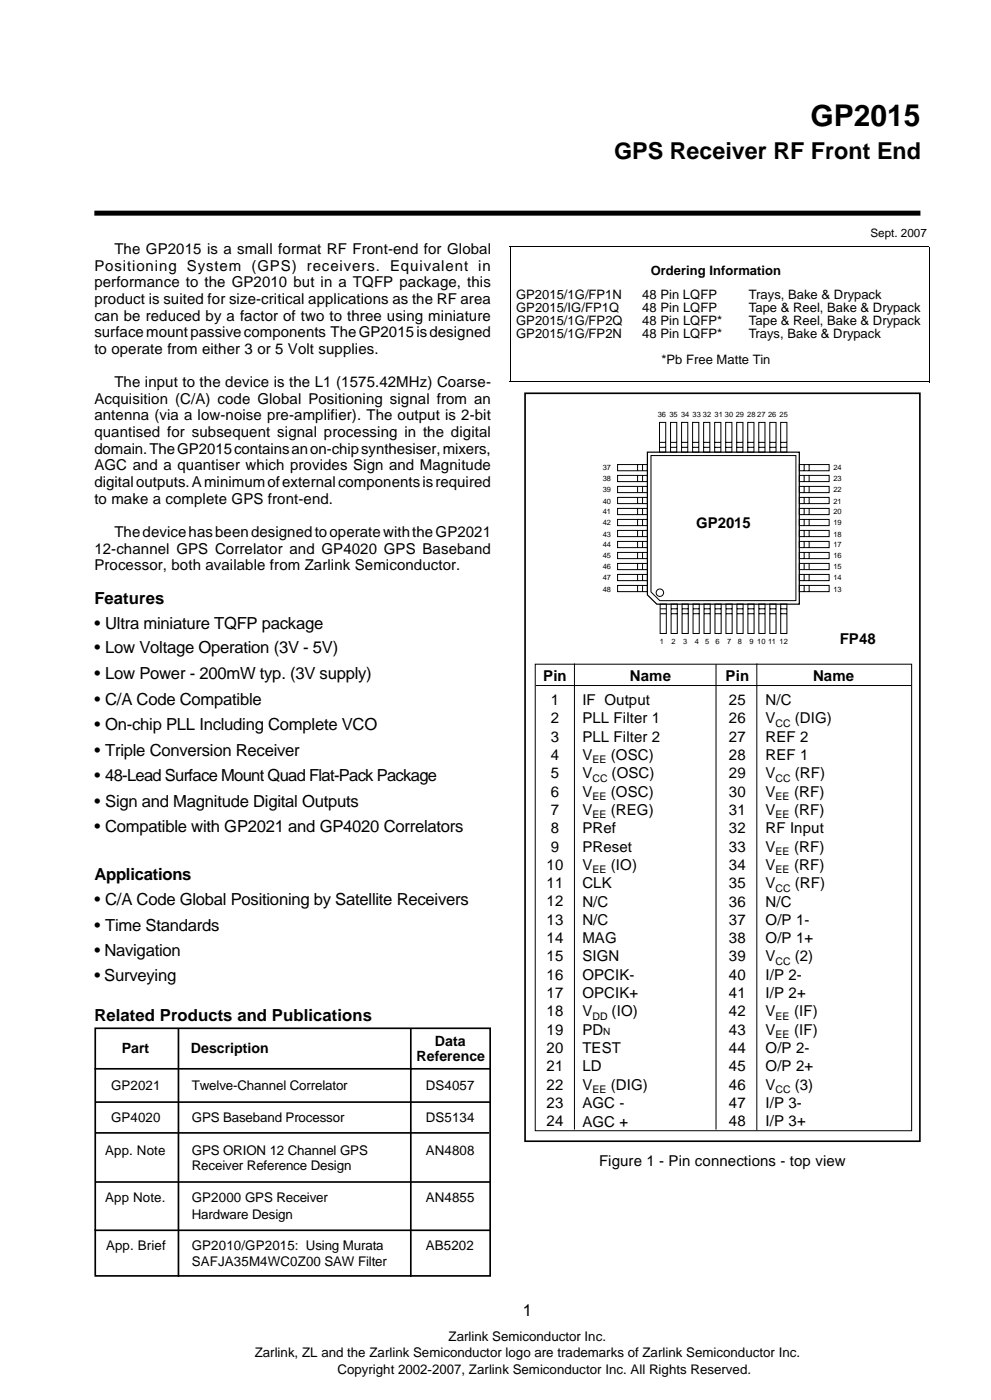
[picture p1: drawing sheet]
<svg xmlns="http://www.w3.org/2000/svg" width="210mm" height="297mm" viewBox="0 0 210 297" stroke-linecap="round" stroke-linejoin="round" font-family="sans-serif">
<defs><g id="words">
<text font-size="6.3" x="171.7" y="26.7">GP2015</text>
<text font-size="4.9" x="130.1" y="33.7">GPS Receiver RF Front End</text>
<g font-size="3.5">
<text x="20" y="127.9">Features</text>
<text x="20" y="133.2">• Ultra miniature TQFP package</text>
<text x="20" y="138.5">• Low Voltage Operation (3V - 5V)</text>
<text x="20" y="144">• Low Power - 200mW typ. (3V supply)</text>
<text x="20" y="149.4">• C/A Code Compatible</text>
<text x="20" y="154.7">• On-chip PLL Including Complete VCO</text>
<text x="20" y="160.2">• Triple Conversion Receiver</text>
<text x="20" y="165.5">• 48-Lead Surface Mount Quad Flat-Pack Package</text>
<text x="20" y="170.9">• Sign and Magnitude Digital Outputs</text>
<text x="20" y="176.4">• Compatible with GP2021 and GP4020 Correlators</text>
<text x="20" y="186.5">Applications</text>
<text x="20" y="191.8">• C/A Code Global Positioning by Satellite Receivers</text>
<text x="20" y="197.2">• Time Standards</text>
<text x="20" y="202.7">• Navigation</text>
<text x="20" y="208">• Surveying</text>
<text x="20" y="216.4">Related Products and Publications</text>
<text x="110.7" y="279">1</text>
</g>
<g font-size="3.2">
<text x="24.2" y="53.8">The GP2015 is a small format RF Front-end for Global</text>
<text x="20" y="57.3">Positioning System (GPS) receivers. Equivalent in</text>
<text x="20" y="60.9">performance to the GP2010 but in a TQFP package, this</text>
<text x="20" y="64.4">product is suited for size-critical applications as the RF area</text>
<text x="20" y="67.9">can be reduced by a factor of two to three using miniature</text>
<text x="20" y="71.5">surface mount passive components The GP2015 is designed</text>
<text x="20" y="75">to operate from either 3 or 5 Volt supplies.</text>
<text x="24.2" y="82">The input to the device is the L1 (1575.42MHz) Coarse-</text>
<text x="20" y="85.6">Acquisition (C/A) code Global Positioning signal from an</text>
<text x="20" y="89.1">antenna (via a low-noise pre-amplifier). The output is 2-bit</text>
<text x="20" y="92.6">quantised for subsequent signal processing in the digital</text>
<text x="20" y="96.1">domain. The GP2015 contains an on-chip synthesiser, mixers,</text>
<text x="20" y="99.7">AGC and a quantiser which provides Sign and Magnitude</text>
<text x="20" y="103.2">digital outputs. A minimum of external components is required</text>
<text x="20" y="106.7">to make a complete GPS front-end.</text>
<text x="24.2" y="113.8">The device has been designed to operate with the GP2021</text>
<text x="147.5" y="112">GP2015</text>
<text x="20" y="117.3">12-channel GPS Correlator and GP4020 GPS Baseband</text>
<text x="20" y="120.8">Processor, both available from Zarlink Semiconductor.</text>
<text x="177.9" y="136.5">FP48</text>
<text x="115.1" y="144.3">Pin</text>
<text x="116.6" y="149.4">1</text>
<text x="123.3" y="149.4">IF Output</text>
<text x="133.4" y="144.3">Name</text>
<text x="153.7" y="144.3">Pin</text>
<text x="154.4" y="149.4">25</text>
<text x="162.2" y="149.4">N/C</text>
<text x="172.2" y="144.3">Name</text>
<text x="116.6" y="153.3">2</text>
<text x="123.3" y="153.3">PLL Filter 1</text>
<text x="154.4" y="153.3">26</text>
<text x="162.2" y="153.3">V</text>
<text x="168.3" y="153.3">(DIG)</text>
<text x="116.6" y="157.2">3</text>
<text x="116.6" y="161.1">4</text>
<text x="123.3" y="157.2">PLL Filter 2</text>
<text x="123.3" y="161.1">V</text>
<text x="129.4" y="161.1">(OSC)</text>
<text x="154.4" y="157.2">27</text>
<text x="154.4" y="161.1">28</text>
<text x="162.2" y="157.2">REF 2</text>
<text x="162.2" y="161.1">REF 1</text>
<text x="116.6" y="164.9">5</text>
<text x="123.3" y="164.9">V</text>
<text x="129.5" y="164.9">(OSC)</text>
<text x="154.4" y="164.9">29</text>
<text x="162.2" y="164.9">V</text>
<text x="168.4" y="164.9">(RF)</text>
<text x="116.6" y="168.8">6</text>
<text x="116.6" y="172.7">7</text>
<text x="123.3" y="168.8">V</text>
<text x="123.3" y="172.7">V</text>
<text x="129.4" y="168.8">(OSC)</text>
<text x="129.4" y="172.7">(REG)</text>
<text x="154.4" y="168.8">30</text>
<text x="154.4" y="172.7">31</text>
<text x="162.2" y="168.8">V</text>
<text x="162.2" y="172.7">V</text>
<text x="168.2" y="168.8">(RF)</text>
<text x="168.2" y="172.7">(RF)</text>
<text x="116.6" y="176.6">8</text>
<text x="123.3" y="176.6">PRef</text>
<text x="154.4" y="176.6">32</text>
<text x="162.2" y="176.6">RF Input</text>
<text x="115.8" y="184.3">10</text>
<text x="116.6" y="180.5">9</text>
<text x="123.3" y="180.5">PReset</text>
<text x="123.3" y="184.3">V</text>
<text x="129.4" y="184.3">(IO)</text>
<text x="154.4" y="180.5">33</text>
<text x="154.4" y="184.3">34</text>
<text x="162.2" y="180.5">V</text>
<text x="162.2" y="184.3">V</text>
<text x="168.2" y="180.5">(RF)</text>
<text x="168.2" y="184.3">(RF)</text>
<text x="115.8" y="188.2">11</text>
<text x="123.3" y="188.2">CLK</text>
<text x="154.4" y="188.2">35</text>
<text x="162.2" y="188.2">V</text>
<text x="168.4" y="188.2">(RF)</text>
<text x="115.8" y="192.1">12</text>
<text x="115.8" y="196">13</text>
<text x="123.3" y="192.1">N/C</text>
<text x="123.3" y="196">N/C</text>
<text x="154.4" y="192.1">36</text>
<text x="154.4" y="196">37</text>
<text x="162.2" y="192.1">N/C</text>
<text x="162.2" y="196">O/P 1-</text>
<text x="115.8" y="199.9">14</text>
<text x="115.8" y="203.7">15</text>
<text x="123.3" y="199.9">MAG</text>
<text x="123.3" y="203.7">SIGN</text>
<text x="154.4" y="199.9">38</text>
<text x="154.4" y="203.7">39</text>
<text x="162.2" y="199.9">O/P 1+</text>
<text x="162.2" y="203.7">V</text>
<text x="168.3" y="203.7">(2)</text>
<text x="115.8" y="207.6">16</text>
<text x="123.3" y="207.6">OPCIK-</text>
<text x="154.4" y="207.6">40</text>
<text x="162.2" y="207.6">I/P 2-</text>
<text x="115.8" y="211.5">17</text>
<text x="115.8" y="215.4">18</text>
<text x="123.3" y="211.5">OPCIK+</text>
<text x="123.3" y="215.4">V</text>
<text x="129.5" y="215.4">(IO)</text>
<text x="154.4" y="211.5">41</text>
<text x="154.4" y="215.4">42</text>
<text x="162.2" y="211.5">I/P 2+</text>
<text x="162.2" y="215.4">V</text>
<text x="168.2" y="215.4">(IF)</text>
<text x="115.8" y="219.3">19</text>
<text x="123.3" y="219.3">PD</text>
<text x="154.4" y="219.3">43</text>
<text x="162.2" y="219.3">V</text>
<text x="168.2" y="219.3">(IF)</text>
<text x="115.8" y="223.1">20</text>
<text x="115.8" y="227">21</text>
<text x="123.3" y="223.1">TEST</text>
<text x="123.3" y="227">LD</text>
<text x="154.4" y="223.1">44</text>
<text x="154.4" y="227">45</text>
<text x="162.2" y="223.1">O/P 2-</text>
<text x="162.2" y="227">O/P 2+</text>
<text x="115.8" y="230.9">22</text>
<text x="123.3" y="230.9">V</text>
<text x="129.4" y="230.9">(DIG)</text>
<text x="154.4" y="230.9">46</text>
<text x="162.2" y="230.9">V</text>
<text x="168.3" y="230.9">(3)</text>
<text x="115.8" y="234.8">23</text>
<text x="115.8" y="238.7">24</text>
<text x="123.3" y="234.8">AGC -</text>
<text x="123.3" y="238.8">AGC +</text>
<text x="154.4" y="234.8">47</text>
<text x="154.4" y="238.7">48</text>
<text x="162.2" y="234.8">I/P 3-</text>
<text x="162.2" y="238.7">I/P 3+</text>
<text x="126.9" y="247.1">Figure 1 - Pin connections - top view</text>
</g>
<g font-size="3">
<text x="92.1" y="221.7">Data</text>
<text x="25.8" y="223.1">Part</text>
<text x="40.4" y="223.1">Description</text>
<text x="88.2" y="224.9">Reference</text>
</g>
<g font-size="2.8">
<text x="137.8" y="58.2">Ordering Information</text>
<text x="109.3" y="63.3">GP2015/1G/FP1N</text>
<text x="136" y="63.3">48 Pin LQFP</text>
<text x="158.6" y="63.3">Trays, Bake &amp; Drypack</text>
<text x="109.3" y="66.2">GP2015/IG/FP1Q</text>
<text x="109.3" y="68.9">GP2015/1G/FP2Q</text>
<text x="109.3" y="71.7">GP2015/1G/FP2N</text>
<text x="136" y="71.7">48 Pin LQFP*</text>
<text x="136" y="68.9">48 Pin LQFP*</text>
<text x="136" y="66.2">48 Pin LQFP</text>
<text x="158.6" y="66.2">Tape &amp; Reel, Bake &amp; Drypack</text>
<text x="158.6" y="71.7">Trays, Bake &amp; Drypack</text>
<text x="158.6" y="68.9">Tape &amp; Reel, Bake &amp; Drypack</text>
<text x="140.1" y="77.2">*Pb Free Matte Tin</text>
<text x="23.5" y="231.1">GP2021</text>
<text x="40.6" y="231.1">Twelve-Channel Correlator</text>
<text x="90.2" y="231.1">DS4057</text>
<text x="23.5" y="237.8">GP4020</text>
<text x="40.6" y="237.8">GPS Baseband Processor</text>
<text x="90.2" y="237.8">DS5134</text>
<text x="22.3" y="244.7">App. Note</text>
<text x="40.6" y="244.7">GPS ORION 12 Channel GPS</text>
<text x="90.2" y="244.7">AN4808</text>
<text x="40.6" y="248">Receiver Reference Design</text>
<text x="22.3" y="254.7">App Note.</text>
<text x="40.6" y="254.7">GP2000 GPS Receiver</text>
<text x="90.2" y="254.7">AN4855</text>
<text x="40.6" y="258.3">Hardware Design</text>
<text x="22.5" y="265">App. Brief</text>
<text x="40.6" y="265">GP2010/GP2015: Using Murata</text>
<text x="40.6" y="268.3">SAFJA35M4WC0Z00 SAW Filter</text>
<text x="90.2" y="265">AB5202</text>
<text x="53.9" y="287.7">Zarlink, ZL and the Zarlink Semiconductor logo are trademarks of Zarlink Semiconductor Inc.</text>
<text x="95" y="284.1">Zarlink Semiconductor Inc.</text>
<text x="71.5" y="291.2">Copyright 2002-2007, Zarlink Semiconductor Inc. All Rights Reserved.</text>
</g>
<text font-size="2.5" x="184.4" y="50.2">Sept. 2007</text>
<g font-size="2.2">
<text x="164.3" y="154">CC</text>
<text x="125.5" y="161.8">EE</text>
<text x="125.5" y="165.6">CC</text>
<text x="164.3" y="165.6">CC</text>
<text x="125.5" y="169.5">EE</text>
<text x="125.5" y="173.4">EE</text>
<text x="164.3" y="169.5">EE</text>
<text x="164.3" y="173.4">EE</text>
<text x="125.5" y="185">EE</text>
<text x="164.3" y="181.2">EE</text>
<text x="164.3" y="185">EE</text>
<text x="164.3" y="188.9">CC</text>
<text x="164.3" y="204.5">CC</text>
<text x="125.5" y="216.1">DD</text>
<text x="164.3" y="216.1">EE</text>
<text x="164.3" y="220">EE</text>
<text x="125.5" y="231.6">EE</text>
<text x="164.3" y="231.6">CC</text>
</g>
<text font-size="2.1" x="127.8" y="219.3">N</text>
<g font-size="1.6">
<text x="139.3" y="88.4">36 35 34 33 32 31 30 29 28 27 26 25</text>
<text x="127.7" y="99.6">37</text>
<text x="127.7" y="102">38</text>
<text x="176.5" y="99.6">24</text>
<text x="176.5" y="102">23</text>
<text x="127.7" y="104.4">39</text>
<text x="127.7" y="106.9">40</text>
<text x="176.5" y="104.4">22</text>
<text x="176.5" y="106.9">21</text>
<text x="127.7" y="109">41</text>
<text x="127.7" y="111.3">42</text>
<text x="127.7" y="113.8">43</text>
<text x="176.5" y="109">20</text>
<text x="176.5" y="111.3">19</text>
<text x="176.5" y="113.8">18</text>
<text x="127.7" y="115.9">44</text>
<text x="127.7" y="118.3">45</text>
<text x="176.5" y="115.9">17</text>
<text x="176.5" y="118.3">16</text>
<text x="127.7" y="120.7">46</text>
<text x="127.7" y="123">47</text>
<text x="127.7" y="125.4">48</text>
<text x="176.5" y="120.7">15</text>
<text x="176.5" y="123">14</text>
<text x="176.5" y="125.4">13</text>
<text x="139.8" y="136.5">1</text>
<text x="142.2" y="136.5">2</text>
<text x="144.7" y="136.5">3</text>
<text x="147.1" y="136.5">4</text>
<text x="149.3" y="136.5">5</text>
<text x="151.5" y="136.5">6</text>
<text x="154" y="136.5">7</text>
<text x="156.3" y="136.5">8</text>
<text x="158.7" y="136.5">9 10 11 12</text>
</g>
</g></defs>
<path d="M20 45.2h175" fill="none" stroke="#000" stroke-width="1.1" stroke-linecap="butt"/>
<path d="M111.2 83.3h83.6v158.5h-83.6zM20.2 217.9h83.6v52.5h-83.6zM37.8 217.9v52.7M87 218v52.6M20 226.5h83.8" fill="none" stroke="#000" stroke-width=".35"/>
<path d="M137.1 95.8h32.2v32.2h-30.2l-2-1.9z" fill="none" stroke="#000" stroke-width=".26"/>
<g fill="none" stroke="#000" stroke-width=".21">
<path d="M139.7 89.5h1.3v6.3h-1.3zM139.7 94.8h1.3M141 93.7h-1.3M142 89.5h1.3v6.3h-1.3zM142 94.8h1.3M142 93.7h1.3M144.4 89.5h1.3v6.3h-1.3zM144.4 94.8h1.3M144.4 93.7h1.3M146.7 89.5h1.3v6.3h-1.3zM146.7 94.8h1.3M146.7 93.7h1.3"/>
<path d="M149 89.5h1.4v6.3h-1.4zM149 94.8h1.4M149 93.7h1.4M151.4 89.5h1.3v6.3h-1.3zM151.4 94.8h1.3M151.4 93.7h1.3M153.7 89.5h1.3v6.3h-1.3zM153.7 94.8h1.3M153.7 93.7h1.3M156 89.5h1.4v6.3h-1.4zM156 94.8h1.4M156 93.7h1.4"/>
<path d="M158.4 89.5h1.3v6.3h-1.3zM158.4 93.7h1.3M159.7 94.8h-1.3M160.7 89.5h1.3v6.3h-1.3zM160.7 94.8h1.3M160.7 93.7h1.3M163.1 89.5h1.3v6.3h-1.3zM163.1 94.8h1.3M163.1 93.7h1.3M130.8 100.7h6.3v1.4h-6.3zM130.8 103.1h6.3v1.3h-6.3zM130.8 105.4h6.3v1.3h-6.3z"/>
<path d="M130.8 107.7h6.3v1.4h-6.3zM130.8 110.1h6.3v1.3h-6.3zM130.8 112.4h6.3v1.3h-6.3zM130.8 114.7h6.3v1.4h-6.3zM130.8 117.1h6.3v1.3h-6.3zM130.8 119.4h6.3v1.3h-6.3zM135 100.7v1.4M135 103.1v1.3M135 105.4v1.3M135 107.7v1.4M135 110.1v1.3M135 112.4v1.3"/>
<path d="M135 114.7v1.4M135 117.1v1.3M135 119.4v1.3M136.1 100.7v1.4M136.1 103.1v1.3M136.1 105.4v1.3M136.1 107.7v1.4M136.1 110.1v1.3M136.1 112.4v1.3M136.1 114.7v1.4M136.1 117.1v1.3M136.1 119.4v1.3"/>
<path d="M169.3 107.7h6.3v1.4h-6.3zM169.3 105.4h6.3v1.3h-6.3zM169.3 103.1h6.3v1.3h-6.3zM169.3 100.7h6.3v1.4h-6.3zM169.3 119.4h6.3v1.3h-6.3zM169.3 117.1h6.3v1.3h-6.3zM169.3 114.7h6.3v1.4h-6.3zM169.3 112.4h6.3v1.3h-6.3zM169.3 110.1h6.3v1.3h-6.3zM170.3 100.7v1.4M170.3 103.1v1.3M170.3 105.4v1.3"/>
<path d="M170.3 107.7v1.4M170.3 110.1v1.3M170.3 112.4v1.3M170.3 114.7v1.4M170.3 117.1v1.3M170.3 119.4v1.3M171.4 100.7v1.4M171.4 103.1v1.3M171.4 105.4v1.3M171.4 107.7v1.4M171.4 110.1v1.3M171.4 112.4v1.3"/>
<path d="M171.4 114.7v1.4M171.4 117.1v1.3M171.4 119.4v1.3M130.8 121.7h6.3v1.3h-6.3zM130.8 124.1h6.3v1.3h-6.3zM135 121.7v1.3M135 124.1v1.3M136.1 121.7v1.3M136.1 124.1v1.3M139.8 128h1.3v6.2h-1.3zM139.8 129h1.3M139.8 130.1h1.3"/>
<path d="M142.1 128h1.4v6.2h-1.4zM142.1 129h1.4M142.1 130.1h1.4M144.5 128h1.3v6.2h-1.3zM144.5 129h1.3M144.5 130.1h1.3M146.8 128h1.3v6.2h-1.3zM146.8 129h1.3M146.8 130.1h1.3M149.1 128h1.3v6.2h-1.3zM149.1 129h1.3M149.1 130.1h1.3"/>
<path d="M151.4 128h1.3v6.2h-1.3zM151.4 129h1.3M151.4 130.1h1.3M153.8 128h1.3v6.2h-1.3zM153.8 129h1.3M153.8 130.1h1.3M156.1 128h1.3v6.2h-1.3zM156.1 130.1h1.3M157.4 129h-1.3M158.4 128h1.3v6.2h-1.3zM158.4 129h1.3M158.4 130.1h1.3"/>
<path d="M160.7 128h1.3v6.2h-1.3zM160.7 129h1.3M160.7 130.1h1.3M163.1 128h1.3v6.2h-1.3zM163.1 129h1.3M164.4 130.1h-1.3M169.3 124.1h6.3v1.3h-6.3zM169.3 121.7h6.3v1.3h-6.3zM170.3 121.7v1.3M170.3 124.1v1.3M171.4 121.7v1.3M171.4 124.1v1.3"/>
</g>
<circle cx="139.8" cy="125.6" r=".79" fill="#fff" stroke="#000" stroke-width=".21"/>
<g fill="none" stroke="#000" stroke-width=".21">
<path d="M107.9 52.3h88.9M108.1 52.2v28.7M196.9 52.3v28.7M107.8 80.9h88.9M130.8 98.4h6.3v1.4h-6.3zM135 98.4v1.4M136.1 98.4v1.4M137.9 96.5h30.7v30.8h-28.8l-1.9-1.9zM165.4 89.5h1.3v6.3h-1.3zM165.4 94.8h1.3M165.4 93.7h1.3M169.3 98.4h6.3v1.4h-6.3z"/>
<path d="M170.3 98.4v1.4M171.4 98.4v1.4M165.4 128h1.3v6.2h-1.3zM165.4 129h1.3M165.4 130.1h1.3M113.4 140.8h79.7v98.8h-79.7zM113.5 145.3h79.5M121.7 140.6v98.8M151.7 140.8v98.6M160.3 140.6v99"/>
</g>
<path d="M20.2 233.6h83.6M20.2 240.1h83.4M20.2 250.5h83.6M20 260.7h83.8" fill="none" stroke="#000" stroke-width=".35"/>
<use href="#words"/>
</svg>
